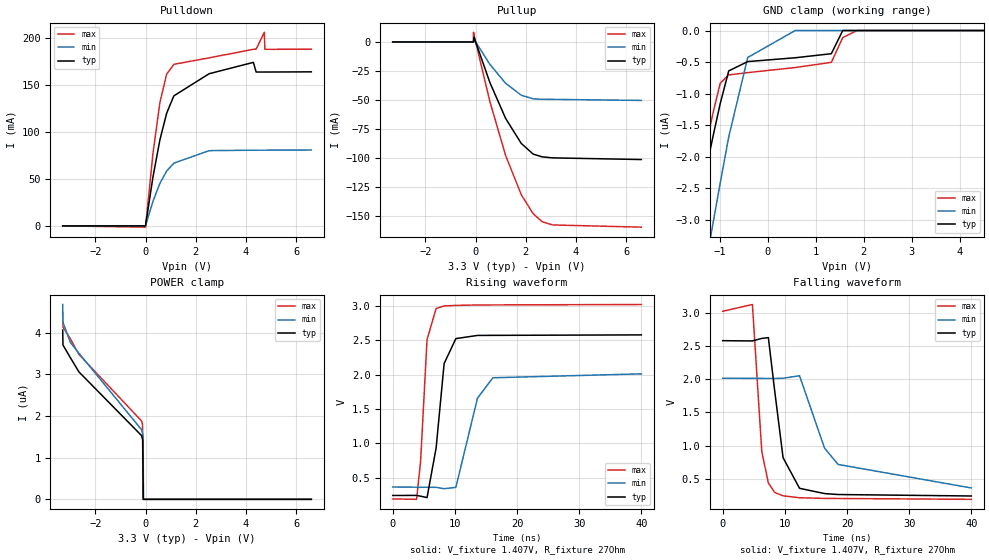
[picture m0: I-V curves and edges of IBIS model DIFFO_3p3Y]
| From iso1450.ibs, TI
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|   DIFFO_3p3Y Model
[Model]   DIFFO_3p3Y
Model_type   3-state
Polarity   Non-Inverting
Vmeas = 1.407
Vref = 1.407
Cref = 2pF
Rref = 27
|   typ   min   max
C_comp   28.160pF   27.902pF   28.290pF
|  Where Nom  PVT is Nominal Process, 3.3V,   27C
|   Fast PVT is Strong Process,  3.6V,   -40C
|   Slow PVT is Weak Process,   3.0V,   150C
[Voltage Range]   3.3   3   3.6
|Junction Temperature
[Temperature Range]   27   150   -40
[Pullup Reference]   3.3   3   3.6
[Pulldown Reference]   -0   0   0
[Power Clamp Reference]   3.3   3   3.6
[GND Clamp Reference]   0   0   0
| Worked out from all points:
|   slope of the pulldown table from 0 to 0.495 V, typ, clamps not added: 6.08 ohm
|   slope of the pullup table from 0 to 0.495 V, typ, clamps not added: 16.1 ohm
|   falling waveform, V_fixture 1.407V, R_fixture 27Ohm: 20-80 % time 2ns typ, 4.59ns min, 1.31ns max; typ from 2.58 V to 0.242 V
|   rising waveform, V_fixture 1.407V, R_fixture 27Ohm: 20-80 % time 1.4ns typ, 2.14ns min, 966ps max; typ from 0.242 V to 2.58 V
[Pulldown]
|   Voltage   I(typ)   I(min)   I(max)
-3.3V     -2.024nA   -51.79nA   -263.5pA
-3.3mV    287.9nA    404.3nA    -1.354mA
293.7mV   51.97mA    26.12mA    77.15mA
570.9mV   91.69mA    45.41mA    131.6mA
838.2mV   119.9mA    58.43mA    161.5mA
1.125V    138.5mA    66.82mA    172.1mA
2.531V    162.1mA    80.16mA    179mA
4.293V    174.2mA    80.62mA    188.1mA
4.402V    163.9mA    80.63mA    188.3mA
4.729V    163.9mA    80.66mA    206.2mA
4.749V    163.9mA    80.67mA    188.1mA
6.6V      164.1mA    80.8mA     188.2mA
[GND Clamp]
|   Voltage   I(typ)   I(min)   I(max)
-3.3V     -10.21uA   -13.17uA   -10.3uA
-1.617V   -3.435uA   -5.128uA   -3.139uA
-1.251V   -2.072uA   -3.524uA   -1.707uA
-1.142V   -1.677uA   -3.055uA   -1.305uA
-993.3mV  -1.16uA    -2.423uA   -835.8nA
-815.1mV  -640.8nA   -1.688uA   -704.8nA
-419.1mV  -493nA     -428nA     -668.1nA
570.9mV   -432.4nA   0A         -587.4nA
1.323V    -368nA     0A         -505.4nA
1.561V    0A         0A         -111.9nA
1.858V    0A         0A         0A
6.6V      0A         0A         0A
[Pullup]
|   Voltage   I(typ)   I(min)   I(max)
-3.3V     94.68uA    89.49uA    108uA
-92.4mV   80.04uA    66.87uA    87.4uA
-82.5mV   77.83uA    66.23uA    8.405mA
-62.7mV   4.363mA    63.7uA     6.186mA
-42.9mV   2.933mA    1.664mA    4.248mA
570.9mV   -34.95mA   -19.27mA   -51.42mA
1.195V    -65.76mA   -35.52mA   -97.73mA
1.818V    -87.38mA   -45.82mA   -131.6mA
2.293V    -96.6mA    -48.92mA   -148mA
2.65V     -98.97mA   -49.36mA   -154.9mA
3.066V    -99.85mA   -49.41mA   -157.7mA
6.6V      -101.3mA   -50.32mA   -159.6mA
[POWER Clamp]
|   Voltage   I(typ)   I(min)   I(max)
-3.3V     4.061uA    4.674uA    4.484uA
-3.29V    3.703uA    4.279uA    4.135uA
-3.27V    3.682uA    4.212uA    4.114uA
-2.993V   3.397uA    3.763uA    3.852uA
-2.656V   3.058uA    3.506uA    3.477uA
-161.7mV  1.53uA     1.672uA    1.881uA
-122.1mV  1.451uA    1.599uA    1.798uA
-112.2mV  1.422uA    1.576uA    899.2nA
-102.3mV  710.9nA    1.55uA     0A
-92.4mV   0A         774.9nA    0A
-82.5mV   0A         0A         0A
6.6V      0A         0A         0A
[Ramp]
R_load = 27
|   typ   min   max
dV/dt_r   1.4018/1.4024e-09   0.98762/2.13973e-09   1.69702/9.64095e-10
dV/dt_f   1.40107/1.99669e-09   0.989926/4.55412e-09   1.69657/1.30729e-09
[Falling Waveform]
V_fixture = 1.407V
V_fixture_min = 1.18V
V_fixture_max = 1.604V
R_fixture = 27Ohm
C_fixture = 0F
|   Time   V(typ)   V(min)   V(max)
0s        2.577V     2.012V     3.019V
4.778ns   2.573V     2.01V      3.121V
6.294ns   2.611V     2.01V      902.8mV
7.347ns   2.623V     2.009V     437.4mV
8.355ns   1.829V     2.009V     295.2mV
9.714ns   817.2mV    2.012V     244.2mV
12.36ns   357.2mV    2.05V      215.1mV
16.38ns   278mV      961.9mV    205.3mV
18.57ns   263.7mV    716mV      204mV
40ns      241.6mV    362.3mV    191.4mV
[Rising Waveform]
V_fixture = 1.407V
V_fixture_min = 1.18V
V_fixture_max = 1.604V
R_fixture = 27Ohm
C_fixture = 0F
|   Time   V(typ)   V(min)   V(max)
0s        241.9mV    364.9mV    191.5mV
3.841ns   242.6mV    362.2mV    185.6mV
4.49ns    231.4mV    361.7mV    740.4mV
5.524ns   210.9mV    361mV      2.51V
6.987ns   934.4mV    359.9mV    2.962V
8.274ns   2.161V     340.6mV    2.999V
10.16ns   2.524V     359.6mV    3.007V
13.64ns   2.57V      1.658V     3.013V
16.12ns   2.571V     1.954V     3.014V
40ns      2.578V     2.011V     3.02V
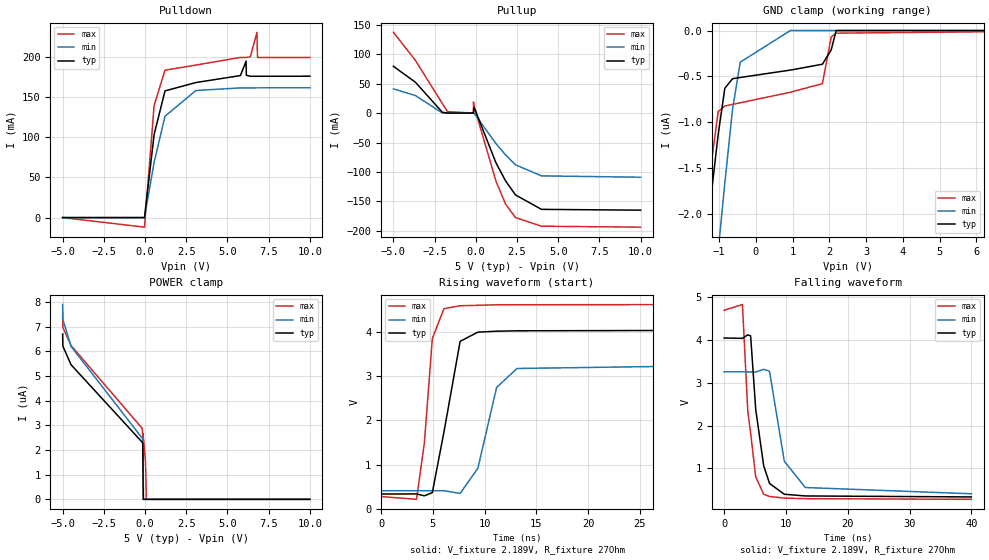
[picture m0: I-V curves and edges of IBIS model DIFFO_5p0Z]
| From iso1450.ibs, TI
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|   DIFFO_5p0Z Model
[Model]   DIFFO_5p0Z
Model_type   3-state
Polarity   Non-Inverting
Vmeas = 2.18852
Vref = 2.18852
Cref = 2pF
Rref = 27
|   typ   min   max
C_comp   26.524pF   26.402pF   26.893pF
|  Where Nom  PVT is Nominal Process, 5.0V,   27C
|   Fast PVT is Strong Process,  5.5V,   -40C
|   Slow PVT is Weak Process,   4.5V,   150C
[Voltage Range]   5   4.5   5.5
|Junction Temperature
[Temperature Range]   27   150   -40
[Pullup Reference]   5   4.5   5.5
[Pulldown Reference]   -0   -0   0
[Power Clamp Reference]   5   4.5   5.5
[GND Clamp Reference]   0   0   0
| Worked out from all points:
|   slope of the pulldown table from 0 to 0.75 V, typ, clamps not added: 5.76 ohm
|   slope of the pullup table from 0 to 0.75 V, typ, clamps not added: 13.7 ohm
|   falling waveform, V_fixture 2.189V, R_fixture 27Ohm: 20-80 % time 1.74ns typ, 2.4ns min, 1.5ns max; typ from 4.04 V to 0.337 V
|   rising waveform, V_fixture 2.189V, R_fixture 27Ohm: 20-80 % time 1.23ns typ, 1.66ns min, 905ps max; typ from 0.338 V to 4.03 V
[Pulldown]
|   Voltage   I(typ)   I(min)   I(max)
-5V       -2.768nA   -62.36nA   -404.6pA
-35mV     425.7nA    561.8nA    -11.95mA
550mV     103.6mA    68.78mA    139.8mA
1.21V     157.9mA    126.3mA    183.7mA
3.085V    168.3mA    158.4mA    190.1mA
5.785V    177mA      161.6mA    199.6mA
6.13V     195mA      161.6mA    199.6mA
6.145V    177.4mA    161.6mA    199.6mA
6.385V    176.1mA    161.6mA    200.3mA
6.79V     176.1mA    161.7mA    230.9mA
6.82V     176.1mA    161.7mA    199.6mA
10V       176.2mA    161.8mA    199.6mA
[GND Clamp]
|   Voltage   I(typ)   I(min)   I(max)
-5V       -16.78uA   -20.83uA   -17.26uA
-1.595V   -3.188uA   -4.867uA   -2.896uA
-1.235V   -1.86uA    -3.297uA   -1.512uA
-1.025V   -1.13uA    -2.4uA     -883.3nA
-845mV    -629.1nA   -1.663uA   -821.7nA
-635mV    -525.4nA   -857.6nA   -804.5nA
-425mV    -511.6nA   -344.6nA   -787.4nA
940mV     -431nA     0A         -672.2nA
1.81V     -367.2nA   0A         -578.8nA
2.05V     -210.5nA   0A         -69.8nA
2.185V    0A         0A         -28.58nA
10V       0A         0A         0A
[Pullup]
|   Voltage   I(typ)   I(min)   I(max)
-5V       79.85mA    41.35mA    137.6mA
-3.665V   52.62mA    30mA       89.9mA
-2.03V    1.545mA    178.1uA    16.37mA
-1.715V   102.2uA    92.32uA    2.543mA
-155mV    86.47uA    72.78uA    97.97uA
-140mV    85.13uA    71.46uA    19mA
-110mV    10.38mA    68.93uA    12.14mA
1.225V    -84.67mA   -51.91mA   -116mA
1.81V     -115.5mA   -71.3mA    -155.1mA
2.41V     -139.3mA   -88mA      -177.8mA
3.985V    -163.8mA   -106.8mA   -192.5mA
10V       -165.2mA   -109.1mA   -194.1mA
[POWER Clamp]
|   Voltage   I(typ)   I(min)   I(max)
-5V       6.707uA    7.907uA    7.452uA
-4.985V   6.207uA    7.35uA     6.964uA
-4.955V   6.17uA     7.231uA    6.927uA
-4.49V    5.462uA    6.208uA    6.245uA
-170mV    2.316uA    2.479uA    2.877uA
-140mV    2.258uA    2.42uA     2.559uA
-125mV    1.129uA    2.383uA    2.672uA
-110mV    0A         1.192uA    1.651uA
-95mV     0A         0A         2.474uA
25mV      0A         0A         1.541uA
85mV      0A         0A         0A
10V       0A         0A         0A
[Ramp]
R_load = 27
|   typ   min   max
dV/dt_r   2.21582/1.21896e-09   1.70645/1.64329e-09   2.5976/9.08052e-10
dV/dt_f   2.22343/1.72147e-09   1.70628/2.38996e-09   2.64494/1.49129e-09
[Falling Waveform]
V_fixture = 2.189V
V_fixture_min = 1.832V
V_fixture_max = 2.483V
R_fixture = 27Ohm
C_fixture = 0F
|   Time   V(typ)   V(min)   V(max)
0s        4.043V     3.254V     4.689V
2.96ns    4.035V     3.254V     4.824V
3.821ns   4.116V     3.253V     2.343V
4.289ns   4.091V     3.251V     1.82V
5.108ns   2.379V     3.249V     804.2mV
6.399ns   1.063V     3.312V     399.3mV
7.343ns   651.5mV    3.269V     347.5mV
9.729ns   399.7mV    1.171V     310.3mV
13.13ns   359.6mV    556.3mV    296.7mV
40ns      337mV      410.4mV    280.9mV
[Rising Waveform]
V_fixture = 2.189V
V_fixture_min = 1.832V
V_fixture_max = 2.483V
R_fixture = 27Ohm
C_fixture = 0F
|   Time   V(typ)   V(min)   V(max)
0s        337.6mV    411.6mV    281mV
3.428ns   339.5mV    412mV      217.8mV
4.189ns   297.3mV    412mV      1.497V
4.952ns   368.6mV    412.1mV    3.839V
6.069ns   1.727V     412.2mV    4.516V
7.638ns   3.779V     351.3mV    4.582V
9.35ns    3.987V     918.5mV    4.592V
11.16ns   4.008V     2.74V      4.603V
13.13ns   4.017V     3.168V     4.604V
40ns      4.031V     3.256V     4.61V
